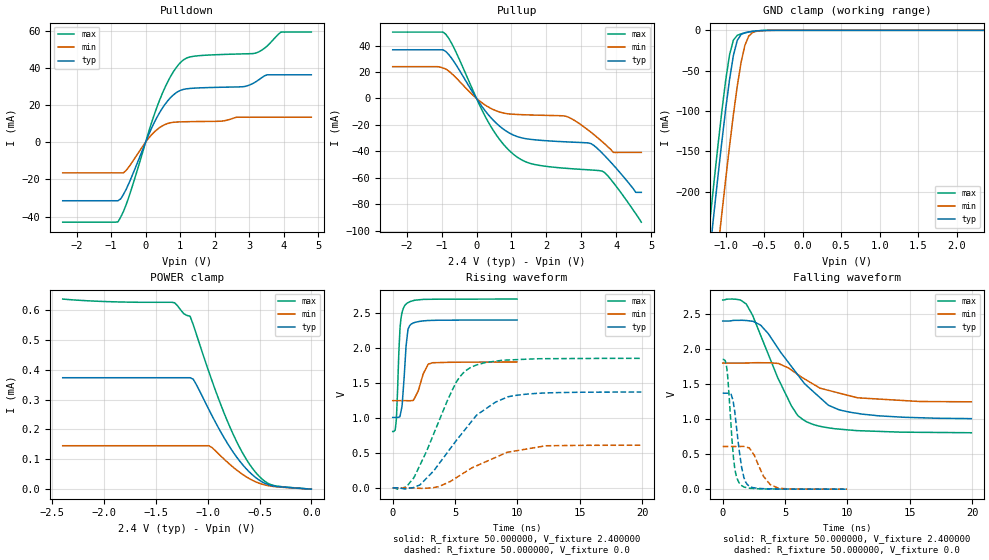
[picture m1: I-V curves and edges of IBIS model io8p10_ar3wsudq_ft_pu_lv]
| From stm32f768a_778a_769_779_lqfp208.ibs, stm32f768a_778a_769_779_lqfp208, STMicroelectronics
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|   Model io8p10_ar3wsudq_ft_pu_lv
[Model]  io8p10_ar3wsudq_ft_pu_lv
Model_type I/O
Polarity   Non-Inverting
Enable   Active-Low
Vinl =   0.720000V
Vinh =   1.680000V
Vmeas =  1.200000V
Cref =   40.000000pF
Rref =   100.000000M
Vref =   0.0V
C_comp   3.720900pF   3.684200pF   3.822900pF
[Temperature Range]   25.000000   0.125000k   -40.000000
[Pullup Reference]   2.400000V   1.800000V   2.700000V
[Pulldown Reference]   0.0V   0.0V   0.0V
[POWER Clamp Reference]   2.400000V   1.800000V   2.700000V
[GND Clamp Reference]   0.0V   0.0V   0.0V
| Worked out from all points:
|   slope of the pulldown table from 0 to 0.36 V, typ, clamps not added: 25 ohm
|   slope of the pullup table from 0 to 0.36 V, typ, clamps not added: 27.7 ohm
|   GND clamp passes 1 mA (typ) near -0.62 V on its own axis
|   rising waveform, R_fixture 50.000000, V_fixture 2.400000: 20-80 % time 333ps typ, 651ps min, 262ps max; typ from 1.01 V to 2.4 V
|   rising waveform, R_fixture 50.000000, V_fixture 0.0: 20-80 % time 3.76ns typ, 4.02ns min, 2.7ns max; typ from 0.001 V to 1.37 V
|   falling waveform, R_fixture 50.000000, V_fixture 2.400000: 20-80 % time 3.91ns typ, 4.04ns min, 2.77ns max; typ from 2.4 V to 1.01 V
|   falling waveform, R_fixture 50.000000, V_fixture 0.0: 20-80 % time 593ps typ, 1.03ns min, 464ps max; typ from 1.37 V to 0.001 V
[Pulldown]
|Voltage   I(typ)   I(min)   I(max)
-2.4V     -31.47mA   -16.45mA   -43.01mA
-800mV    -31.47mA   -16.45mA   -42.85mA
-480mV    -21.98mA   -13.17mA   -29.21mA
80mV      3.63mA     1.966mA    5.014mA
480mV     18.16mA    8.738mA    26.02mA
800mV     25.38mA    10.72mA    37.77mA
1.12V     28.53mA    11.02mA    44.6mA
2.8V      29.84mA    13.47mA    47.53mA
3.2V      32.6mA     13.47mA    48.03mA
3.52V     36.29mA    13.47mA    51.75mA
3.92V     36.29mA    13.47mA    59.26mA
4.8V      36.29mA    13.47mA    59.26mA
[Pullup]
|Voltage   I(typ)   I(min)   I(max)
-2.4V     36.82mA    24.03mA    50.21mA
-960mV    36.82mA    23mA       50.21mA
-640mV    27.62mA    17.03mA    37.94mA
320mV     -11.75mA   -6.207mA   -17.08mA
960mV     -26.47mA   -11.82mA   -40.02mA
1.52V     -30.88mA   -12.51mA   -49.05mA
2.56V     -32.88mA   -13.52mA   -52.9mA
3.28V     -34.25mA   -25.64mA   -54.17mA
3.6V      -41.44mA   -32.74mA   -55.02mA
3.92V     -50.46mA   -40.9mA    -63.78mA
4.56V     -71.1mA    -40.9mA    -87.26mA
4.72V     -71.1mA    -40.9mA    -93.7mA
[GND_clamp]
|Voltage   I(typ)   I(min)   I(max)
-2.4V     -1.43A     -1.515A    -1.399A
-1.25V    -315.9mA   -407.2mA   -278.2mA
-1.2V     -270.1mA   -361.3mA   -232.1mA
-1.15V    -225mA     -316mA     -186.8mA
-1.1V     -180.9mA   -271.3mA   -142.7mA
-1.05V    -138.2mA   -227.5mA   -100.5mA
-950mV    -61.14mA   -143.6mA   -30.43mA
-900mV    -31.23mA   -104.7mA   -12.14mA
-850mV    -12.49mA   -69.4mA    -6.221mA
-750mV    -2.898mA   -18.35mA   -3.18mA
-600mV    -750.2uA   -1.218mA   -738.3uA
2.35V     0A         0A         0A
[POWER_clamp]
|Voltage   I(typ)   I(min)   I(max)
-2.4V     373.1uA    145.5uA    636.5uA
-1.32V    373.1uA    145.5uA    624.2uA
-1.23V    373.1uA    145.5uA    587.2uA
-1.17V    373.1uA    145.5uA    579uA
-1.14V    368.3uA    145.5uA    550.7uA
-990mV    267.3uA    145.5uA    393.9uA
-810mV    153.6uA    90.29uA    227.7uA
-690mV    93.37uA    55.97uA    138.2uA
-570mV    48.37uA    29.94uA    70.44uA
-480mV    25.27uA    17.04uA    35.17uA
-390mV    12.49uA    10.18uA    15.16uA
0V        0A         0A         0A
[Ramp]
| variable   typ   min   max
dV/dt_r  0.82195/3.76236n   0.36591/4.02215n   1.11287/2.70274n
dV/dt_f  0.83262/3.90875n   0.33210/4.10871n   1.13572/2.76916n
R_load = 50.000000
[Rising Waveform]
R_fixture= 50.000000
V_fixture= 2.400000
V_fixture_min= 1.800000
V_fixture_max= 2.700000
|time   V(typ)   V(min)   V(max)
0s        1.007V     1.247V     805.9mV
200.2ps   1.007V     1.247V     831.6mV
280.3ps   1.007V     1.247V     953.6mV
580.6ps   1.02V      1.247V     2.266V
760.8ps   1.194V     1.247V     2.513V
1.021ns   1.882V     1.247V     2.619V
1.241ns   2.273V     1.246V     2.649V
1.762ns   2.364V     1.287V     2.683V
2.863ns   2.393V     1.77V      2.696V
9.97ns    2.4V       1.8V       2.699V
[Rising Waveform]
R_fixture= 50.000000
V_fixture= 0.0
V_fixture_min= 0.0
V_fixture_max= 0.0
|time   V(typ)   V(min)   V(max)
0s        1.04mV     904.1uV    1.025mV
1.081ns   -12.03mV   963.1uV    15.4mV
1.682ns   6.771mV    -78.99uV   142.4mV
3.283ns   243.2mV    4.878mV    770.6mV
5.045ns   665.1mV    140mV      1.496V
6.366ns   960mV      287.9mV    1.731V
8.248ns   1.226V     435.9mV    1.811V
9.61ns    1.315V     521.9mV    1.831V
12.29ns   1.357V     602.5mV    1.847V
19.94ns   1.371V     610.2mV    1.852V
[Falling Waveform]
R_fixture= 50.000000
V_fixture= 2.400000
V_fixture_min= 1.800000
V_fixture_max= 2.700000
|time   V(typ)   V(min)   V(max)
0s        2.4V       1.8V       2.699V
1.361ns   2.41V      1.8V       2.702V
1.882ns   2.407V     1.801V     2.644V
3.043ns   2.341V     1.805V     2.196V
4.484ns   1.998V     1.794V     1.565V
5.526ns   1.748V     1.699V     1.185V
6.687ns   1.486V     1.561V     966.1mV
8.488ns   1.198V     1.41V      876.3mV
10.17ns   1.1V       1.334V     844.9mV
19.94ns   1.007V     1.247V     805.9mV
[Falling Waveform]
R_fixture= 50.000000
V_fixture= 0.0
V_fixture_min= 0.0
V_fixture_max= 0.0
|time   V(typ)   V(min)   V(max)
0s        1.371V     610.2mV    1.852V
320.3ps   1.371V     610.2mV    1.736V
820.8ps   1.272V     610mV      540.8mV
1.061ns   955.8mV    609.8mV    209.5mV
1.421ns   432.1mV    610.3mV    67.14mV
1.702ns   166.2mV    609.8mV    33.21mV
2.062ns   53.3mV     593mV      17.42mV
3.283ns   7.662mV    181.9mV    4.683mV
4.464ns   3.223mV    15.27mV    2.145mV
9.97ns    1.04mV     904.1uV    1.025mV
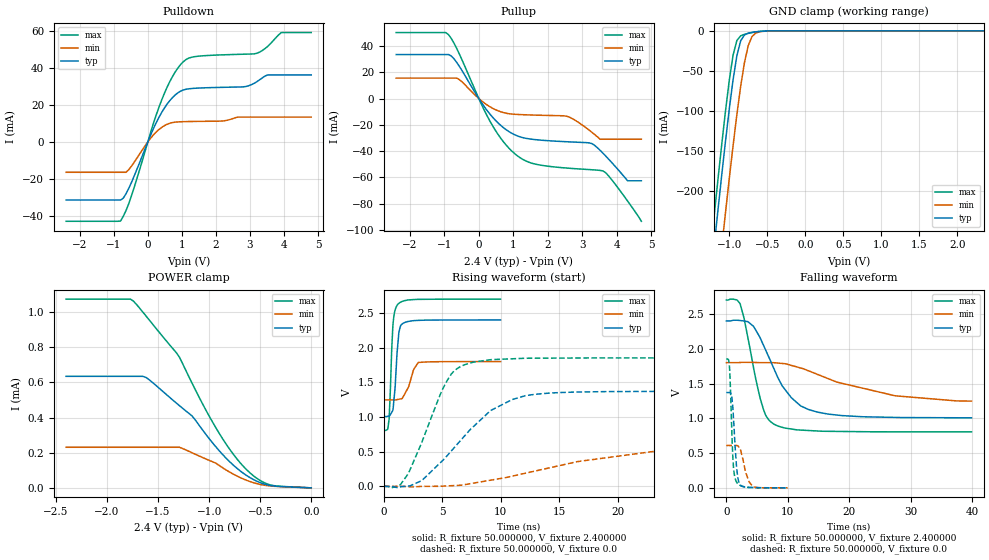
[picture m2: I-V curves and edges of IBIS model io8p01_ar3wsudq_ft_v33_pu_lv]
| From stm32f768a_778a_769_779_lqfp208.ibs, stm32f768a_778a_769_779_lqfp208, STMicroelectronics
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|   Model io8p01_ar3wsudq_ft_v33_pu_lv
[Model]  io8p01_ar3wsudq_ft_v33_pu_lv
Model_type I/O
Polarity   Non-Inverting
Enable   Active-Low
Vinl =   0.720000V
Vinh =   1.680000V
Vmeas =  1.200000V
Cref =   50.000000pF
Rref =   100.000000M
Vref =   0.0V
C_comp   3.737900pF   3.690400pF   3.817400pF
[Temperature Range]   25.000000   0.125000k   -40.000000
[Pullup Reference]   2.400000V   1.800000V   2.700000V
[Pulldown Reference]   0.0V   0.0V   0.0V
[POWER Clamp Reference]   2.400000V   1.800000V   2.700000V
[GND Clamp Reference]   0.0V   0.0V   0.0V
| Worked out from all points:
|   slope of the pulldown table from 0 to 0.36 V, typ, clamps not added: 25 ohm
|   slope of the pullup table from 0 to 0.36 V, typ, clamps not added: 27.7 ohm
|   GND clamp passes 1 mA (typ) near -0.62 V on its own axis
|   rising waveform, R_fixture 50.000000, V_fixture 2.400000: 20-80 % time 349ps typ, 697ps min, 271ps max; typ from 1.01 V to 2.4 V
|   rising waveform, R_fixture 50.000000, V_fixture 0.0: 20-80 % time 4.74ns typ, 12.1ns min, 2.7ns max; typ from 0.001 V to 1.37 V
|   falling waveform, R_fixture 50.000000, V_fixture 2.400000: 20-80 % time 5.04ns typ, 12.6ns min, 2.7ns max; typ from 2.4 V to 1.01 V
|   falling waveform, R_fixture 50.000000, V_fixture 0.0: 20-80 % time 601ps typ, 1.08ns min, 463ps max; typ from 1.37 V to 0.001 V
[Pulldown]
|Voltage   I(typ)   I(min)   I(max)
-2.4V     -31.47mA   -16.45mA   -43.01mA
-800mV    -31.47mA   -16.45mA   -42.85mA
-480mV    -21.98mA   -13.17mA   -29.21mA
80mV      3.63mA     1.966mA    5.014mA
480mV     18.16mA    8.738mA    26.02mA
800mV     25.38mA    10.72mA    37.77mA
1.12V     28.53mA    11.02mA    44.6mA
2.8V      29.84mA    13.47mA    47.53mA
3.2V      32.6mA     13.47mA    48.03mA
3.52V     36.3mA     13.47mA    51.75mA
3.92V     36.3mA     13.47mA    59.27mA
4.8V      36.3mA     13.47mA    59.27mA
[Pullup]
|Voltage   I(typ)   I(min)   I(max)
-2.4V     33.5mA     15.56mA    50.21mA
-960mV    33.5mA     15.56mA    50.21mA
-800mV    32.39mA    15.56mA    45.69mA
-560mV    24.27mA    14.3mA     33.51mA
320mV     -11.75mA   -6.207mA   -17.08mA
960mV     -26.47mA   -11.82mA   -40.02mA
1.52V     -30.88mA   -12.51mA   -49.05mA
2.56V     -32.88mA   -13.52mA   -52.9mA
3.28V     -34.25mA   -25.62mA   -54.17mA
3.6V      -41.44mA   -30.96mA   -55.02mA
4.32V     -62.57mA   -30.96mA   -77.98mA
4.72V     -62.57mA   -30.96mA   -93.4mA
[GND_clamp]
|Voltage   I(typ)   I(min)   I(max)
-2.4V     -1.437A    -1.518A    -1.411A
-1.25V    -315.9mA   -407.2mA   -278.2mA
-1.2V     -270.1mA   -361.3mA   -232.1mA
-1.15V    -225mA     -316mA     -186.8mA
-1.1V     -180.9mA   -271.3mA   -142.7mA
-1.05V    -138.2mA   -227.5mA   -100.5mA
-950mV    -61.14mA   -143.6mA   -30.43mA
-900mV    -31.23mA   -104.7mA   -12.14mA
-850mV    -12.49mA   -69.4mA    -6.221mA
-750mV    -2.898mA   -18.35mA   -3.18mA
-600mV    -750.2uA   -1.218mA   -738.3uA
2.35V     0A         0A         0A
[POWER_clamp]
|Voltage   I(typ)   I(min)   I(max)
-2.4V     634.4uA    230.9uA    1.073mA
-1.77V    634.4uA    230.9uA    1.073mA
-1.74V    634.4uA    230.9uA    1.062mA
-1.62V    628.7uA    230.9uA    979.3uA
-1.29V    467.4uA    230.9uA    743.1uA
-1.17V    410.9uA    200.6uA    599.2uA
-930mV    230.8uA    139uA      338.2uA
-780mV    138.4uA    83.46uA    204.6uA
-660mV    81.05uA    49.28uA    119.5uA
-540mV    39.7uA     25.07uA    57.27uA
-420mV    15.59uA    11.9uA     19.92uA
0V        0A         0A         0A
[Ramp]
| variable   typ   min   max
dV/dt_r  0.82231/4.74010n   0.38222/12.88778n   1.11089/2.69821n
dV/dt_f  0.83616/5.04470n   0.32160/12.69214n   1.13688/2.70258n
R_load = 50.000000
[Rising Waveform]
R_fixture= 50.000000
V_fixture= 2.400000
V_fixture_min= 1.800000
V_fixture_max= 2.700000
|time   V(typ)   V(min)   V(max)
0s        1.007V     1.247V     806mV
320.3ps   1.011V     1.247V     822.7mV
440.4ps   1.016V     1.247V     969.4mV
660.7ps   1.067V     1.247V     1.96V
760.8ps   1.097V     1.247V     2.308V
961ps     1.445V     1.247V     2.545V
1.201ns   2.076V     1.254V     2.628V
1.441ns   2.323V     1.263V     2.658V
2.943ns   2.393V     1.787V     2.696V
9.97ns    2.4V       1.8V       2.7V
[Rising Waveform]
R_fixture= 50.000000
V_fixture= 0.0
V_fixture_min= 0.0
V_fixture_max= 0.0
|time   V(typ)   V(min)   V(max)
0s        967.4uV    875.8uV    1.107mV
1.441ns   -3.909mV   396.7uV    32.55mV
3.203ns   82.27mV    359.1uV    620.7mV
5.365ns   435.5mV    7.37mV     1.514V
6.246ns   604mV      14.66mV    1.696V
7.608ns   855.7mV    46.22mV    1.79V
9.129ns   1.095V     90.07mV    1.827V
13.13ns   1.331V     229.5mV    1.849V
25.23ns   1.371V     552.7mV    1.852V
39.88ns   1.371V     610.3mV    1.852V
[Falling Waveform]
R_fixture= 50.000000
V_fixture= 2.400000
V_fixture_min= 1.800000
V_fixture_max= 2.700000
|time   V(typ)   V(min)   V(max)
0s        2.4V       1.8V       2.7V
2.242ns   2.405V     1.802V     2.646V
4.404ns   2.324V     1.804V     1.738V
5.526ns   2.152V     1.801V     1.281V
6.486ns   1.963V     1.8V       1.032V
7.768ns   1.708V     1.799V     915.5mV
10.57ns   1.297V     1.761V     846.7mV
14.81ns   1.09V      1.632V     818.1mV
27.47ns   1.013V     1.324V     806.5mV
39.88ns   1.007V     1.247V     806mV
[Falling Waveform]
R_fixture= 50.000000
V_fixture= 0.0
V_fixture_min= 0.0
V_fixture_max= 0.0
|time   V(typ)   V(min)   V(max)
0s        1.371V     610.3mV    1.852V
460.5ps   1.371V     610.2mV    1.796V
660.7ps   1.368V     610.1mV    1.449V
860.9ps   1.329V     609.9mV    893.9mV
1.161ns   1.006V     609.7mV    303.4mV
1.602ns   377.1mV    609.7mV    94.62mV
2.222ns   49.9mV     568.8mV    37.55mV
3.143ns   11.7mV     224.6mV    13.38mV
4.344ns   5.49mV     15.82mV    5.194mV
9.97ns    967.4uV    875.8uV    1.107mV
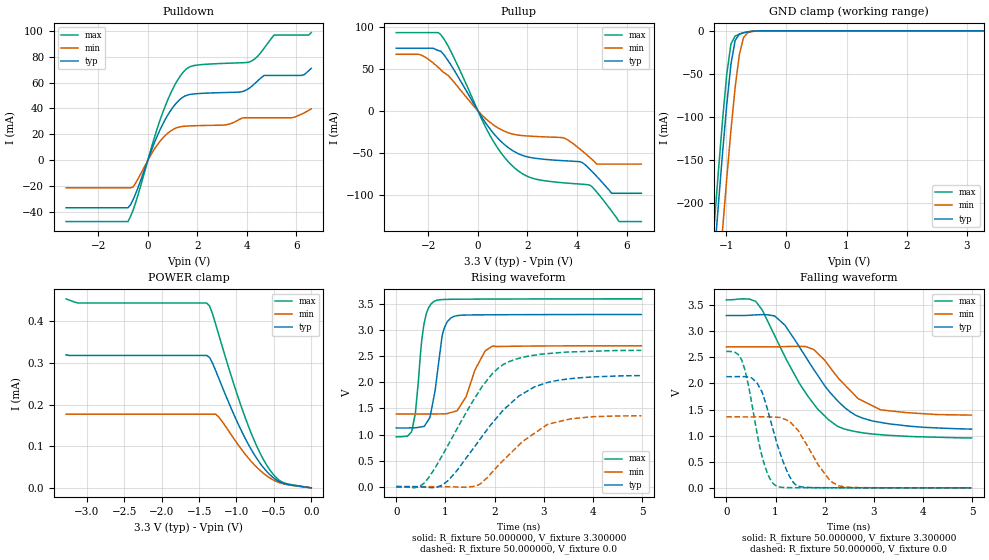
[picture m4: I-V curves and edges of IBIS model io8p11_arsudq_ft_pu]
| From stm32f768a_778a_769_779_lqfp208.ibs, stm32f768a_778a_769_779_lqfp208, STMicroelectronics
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|   Model io8p11_arsudq_ft_pu
[Model]  io8p11_arsudq_ft_pu
Model_type I/O
Polarity   Non-Inverting
Enable   Active-Low
Vinl =   0.990000V
Vinh =   2.310000V
Vmeas =  1.650000V
Cref =   30.000000pF
Rref =   100.000000M
Vref =   0.0V
C_comp   2.292100pF   2.228000pF   2.366600pF
[Temperature Range]   25.000000   0.125000k   -40.000000
[Pullup Reference]   3.300000V   2.700000V   3.600000V
[Pulldown Reference]   0.0V   0.0V   0.0V
[POWER Clamp Reference]   3.300000V   2.700000V   3.600000V
[GND Clamp Reference]   0.0V   0.0V   0.0V
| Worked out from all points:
|   slope of the pulldown table from 0 to 0.495 V, typ, clamps not added: 20.9 ohm
|   slope of the pullup table from 0 to 0.495 V, typ, clamps not added: 22.6 ohm
|   GND clamp passes 1 mA (typ) near -0.62 V on its own axis
|   rising waveform, R_fixture 50.000000, V_fixture 3.300000: 20-80 % time 196ps typ, 341ps min, 160ps max; typ from 1.12 V to 3.3 V
|   rising waveform, R_fixture 50.000000, V_fixture 0.0: 20-80 % time 1.13ns typ, 965ps min, 999ps max; typ from 0.001 V to 2.13 V
|   falling waveform, R_fixture 50.000000, V_fixture 3.300000: 20-80 % time 1.01ns typ, 790ps min, 981ps max; typ from 3.3 V to 1.12 V
|   falling waveform, R_fixture 50.000000, V_fixture 0.0: 20-80 % time 415ps typ, 536ps min, 331ps max; typ from 2.13 V to 0.001 V
[Pulldown]
|Voltage   I(typ)   I(min)   I(max)
-3.3V     -36.46mA   -21.09mA   -47.09mA
-800mV    -36.46mA   -21.09mA   -47.09mA
-600mV    -30.5mA    -20.55mA   -38.69mA
700mV     31.4mA     19.11mA    41.71mA
1.2V      45.15mA    25.37mA    61.75mA
1.6V      50.35mA    26.5mA     71.06mA
3.1V      52.28mA    27.26mA    74.76mA
4.1V      55.64mA    32.87mA    75.8mA
4.7V      65.47mA    32.87mA    86.49mA
5.1V      65.47mA    32.87mA    96.56mA
6.2V      65.47mA    35.57mA    96.56mA
6.6V      70.92mA    39.71mA    98.46mA
[Pullup]
|Voltage   I(typ)   I(min)   I(max)
-3.3V     74.7mA     67.42mA    93.32mA
-2.3V     74.7mA     66.58mA    93.32mA
-1.5V     71.16mA    49mA       90.81mA
500mV     -22.06mA   -14mA      -30.03mA
1.6V      -50.64mA   -28.81mA   -70.96mA
3.5V      -59.52mA   -32.65mA   -85.91mA
4.2V      -61.43mA   -47.48mA   -87.45mA
4.5V      -69.07mA   -55.12mA   -88.37mA
4.8V      -78.22mA   -63.5mA    -96.83mA
5.4V      -98.3mA    -63.5mA    -119.6mA
5.7V      -98.3mA    -63.5mA    -132mA
6.6V      -98.3mA    -63.5mA    -132mA
[GND_clamp]
|Voltage   I(typ)   I(min)   I(max)
-3.3V     -2.316A    -2.396A    -2.289A
-1.2V     -265.5mA   -356.1mA   -227.2mA
-1.13V    -202.6mA   -292.9mA   -164.1mA
-1.06V    -142.2mA   -231.2mA   -104.1mA
-990mV    -85.98mA   -171.6mA   -50.72mA
-920mV    -38.8mA    -115.5mA   -15.28mA
-850mV    -11.08mA   -65.6mA    -6.001mA
-780mV    -3.782mA   -27.42mA   -3.876mA
-710mV    -2.086mA   -7.69mA    -2.381mA
-640mV    -1.147mA   -2.118mA   -1.22mA
-570mV    -523.9uA   -798.4uA   -476.8uA
3.28V     0A         0A         0A
[POWER_clamp]
|Voltage   I(typ)   I(min)   I(max)
-3.28V    319.9uA    177.1uA    454.3uA
-3.12V    318.3uA    177.1uA    444.3uA
-1.4V     318.3uA    177.1uA    444.3uA
-1.36V    313.4uA    177.1uA    437.2uA
-1.28V    282.3uA    177.1uA    394.1uA
-1.24V    264.6uA    170.9uA    369.7uA
-920mV    131.9uA    89.35uA    187.2uA
-760mV    79.47uA    55.13uA    112.7uA
-640mV    48.78uA    35.04uA    68.06uA
-520mV    26.21uA    20.11uA    35uA
-400mV    12.52uA    10.81uA    14.88uA
0V        0A         0A         0A
[Ramp]
| variable   typ   min   max
dV/dt_r  1.26121/1.11649n   0.80589/0.95701n   1.56034/0.99718n
dV/dt_f  1.27626/0.99385n   0.77838/0.78710n   1.56923/0.97409n
R_load = 50.000000
[Rising Waveform]
R_fixture= 50.000000
V_fixture= 3.300000
V_fixture_min= 2.700000
V_fixture_max= 3.600000
|time   V(typ)   V(min)   V(max)
0s        1.125V     1.393V     955.6mV
320.3ps   1.128V     1.393V     1.08V
390.4ps   1.129V     1.393V     1.416V
560.6ps   1.154V     1.393V     3.091V
690.7ps   1.346V     1.393V     3.478V
780.8ps   1.791V     1.393V     3.556V
951ps     2.958V     1.396V     3.586V
1.171ns   3.263V     1.437V     3.591V
1.962ns   3.294V     2.695V     3.595V
4.985ns   3.3V       2.7V       3.599V
[Rising Waveform]
R_fixture= 50.000000
V_fixture= 0.0
V_fixture_min= 0.0
V_fixture_max= 0.0
|time   V(typ)   V(min)   V(max)
0s        1.434mV    1.24mV     1.788mV
470.5ps   -1.714mV   1.179mV    3.241mV
650.7ps   -12.8mV    1.241mV    161.4mV
951ps     40.95mV    15.87uV    623.8mV
1.662ns   854.4mV    29.47mV    1.793V
2.182ns   1.473V     508.9mV    2.343V
2.492ns   1.736V     795.9mV    2.46V
3.083ns   1.998V     1.197V     2.55V
4.004ns   2.103V     1.342V     2.595V
4.985ns   2.129V     1.359V     2.612V
[Falling Waveform]
R_fixture= 50.000000
V_fixture= 3.300000
V_fixture_min= 2.700000
V_fixture_max= 3.600000
|time   V(typ)   V(min)   V(max)
0s        3.3V       2.7V       3.599V
600.6ps   3.312V     2.7V       3.567V
730.7ps   3.316V     2.7V       3.403V
981ps     3.291V     2.701V     2.918V
1.191ns   3.115V     2.704V     2.512V
1.772ns   2.275V     2.651V     1.614V
2.262ns   1.668V     2.118V     1.179V
2.683ns   1.37V      1.707V     1.068V
3.133ns   1.255V     1.495V     1.018V
4.985ns   1.125V     1.393V     955.6mV
[Falling Waveform]
R_fixture= 50.000000
V_fixture= 0.0
V_fixture_min= 0.0
V_fixture_max= 0.0
|time   V(typ)   V(min)   V(max)
0s        2.129V     1.359V     2.612V
310.3ps   2.13V      1.359V     2.454V
450.5ps   2.119V     1.359V     1.96V
720.7ps   1.844V     1.36V      626.8mV
880.9ps   1.352V     1.36V      186.7mV
1.011ns   914mV      1.353V     40.95mV
1.391ns   75.04mV    1.169V     4.403mV
1.872ns   4.587mV    436.1mV    3.191mV
2.282ns   2.973mV    41.02mV    2.805mV
4.985ns   1.434mV    1.24mV     1.788mV
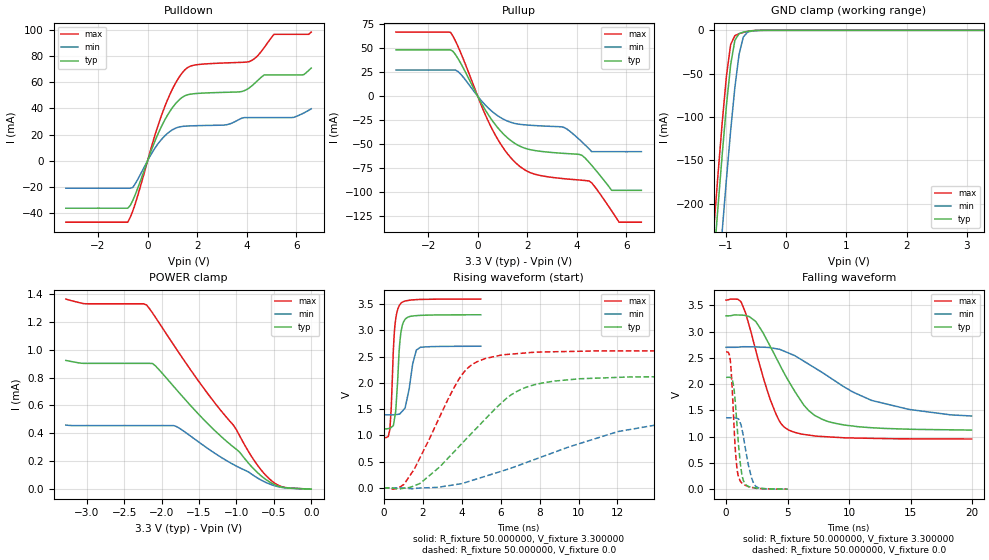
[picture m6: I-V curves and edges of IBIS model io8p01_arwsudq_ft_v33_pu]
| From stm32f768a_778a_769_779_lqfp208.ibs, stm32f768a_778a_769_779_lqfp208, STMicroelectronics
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|   Model io8p01_arwsudq_ft_v33_pu
[Model]  io8p01_arwsudq_ft_v33_pu
Model_type I/O
Polarity   Non-Inverting
Enable   Active-Low
Vinl =   0.990000V
Vinh =   2.310000V
Vmeas =  1.650000V
Cref =   50.000000pF
Rref =   100.000000M
Vref =   0.0V
C_comp   2.911600pF   2.826700pF   2.983100pF
[Temperature Range]   25.000000   0.125000k   -40.000000
[Pullup Reference]   3.300000V   2.700000V   3.600000V
[Pulldown Reference]   0.0V   0.0V   0.0V
[POWER Clamp Reference]   3.300000V   2.700000V   3.600000V
[GND Clamp Reference]   0.0V   0.0V   0.0V
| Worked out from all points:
|   slope of the pulldown table from 0 to 0.495 V, typ, clamps not added: 20.9 ohm
|   slope of the pullup table from 0 to 0.495 V, typ, clamps not added: 22.6 ohm
|   GND clamp passes 1 mA (typ) near -0.62 V on its own axis
|   rising waveform, R_fixture 50.000000, V_fixture 3.300000: 20-80 % time 219ps typ, 367ps min, 188ps max; typ from 1.12 V to 3.3 V
|   rising waveform, R_fixture 50.000000, V_fixture 0.0: 20-80 % time 3.35ns typ, 6.59ns min, 2.1ns max; typ from 0.001 V to 2.13 V
|   falling waveform, R_fixture 50.000000, V_fixture 3.300000: 20-80 % time 3.22ns typ, 6.15ns min, 2.03ns max; typ from 3.3 V to 1.12 V
|   falling waveform, R_fixture 50.000000, V_fixture 0.0: 20-80 % time 464ps typ, 672ps min, 373ps max; typ from 2.13 V to 0.001 V
[Pulldown]
|Voltage   I(typ)   I(min)   I(max)
-3.3V     -36.38mA   -21.07mA   -47.09mA
-800mV    -36.38mA   -21.07mA   -47.09mA
-600mV    -30.5mA    -20.54mA   -38.69mA
700mV     31.4mA     19.11mA    41.71mA
1.2V      45.15mA    25.37mA    61.75mA
1.6V      50.35mA    26.5mA     71.06mA
3.1V      52.28mA    27.26mA    74.76mA
4.1V      55.65mA    32.94mA    75.79mA
4.7V      65.59mA    32.94mA    86.49mA
5.1V      65.59mA    32.94mA    96.67mA
6.3V      65.82mA    36.48mA    96.67mA
6.6V      70.87mA    39.69mA    98.38mA
[Pullup]
|Voltage   I(typ)   I(min)   I(max)
-3.3V     48.41mA    27.39mA    66.93mA
-1.1V     48.41mA    27.39mA    66.7mA
-700mV    35.09mA    23.45mA    46.27mA
500mV     -22.06mA   -14mA      -30.03mA
1.5V      -49.1mA    -28.3mA    -68.56mA
2.2V      -56.04mA   -30.32mA   -80.35mA
3.5V      -59.52mA   -32.65mA   -85.91mA
4.2V      -61.45mA   -47.47mA   -87.45mA
4.5V      -69.09mA   -55.01mA   -88.4mA
5.4V      -98mA      -57.7mA    -119.3mA
5.7V      -98mA      -57.7mA    -131.2mA
6.6V      -98mA      -57.7mA    -131.2mA
[GND_clamp]
|Voltage   I(typ)   I(min)   I(max)
-3.3V     -2.32A     -2.397A    -2.297A
-1.2V     -266.4mA   -356.3mA   -229.4mA
-1.13V    -203.6mA   -293.1mA   -166.3mA
-1.06V    -143.2mA   -231.4mA   -106.2mA
-990mV    -86.95mA   -171.8mA   -52.65mA
-920mV    -39.66mA   -115.8mA   -16.36mA
-850mV    -11.49mA   -65.84mA   -6.11mA
-780mV    -3.834mA   -27.59mA   -3.88mA
-710mV    -2.09mA    -7.753mA   -2.381mA
-640mV    -1.147mA   -2.129mA   -1.22mA
-570mV    -523.9uA   -800uA     -476.8uA
3.28V     0A         0A         0A
[POWER_clamp]
|Voltage   I(typ)   I(min)   I(max)
-3.28V    922.4uA    459.4uA    1.362mA
-3.04V    901.4uA    455.8uA    1.329mA
-2.2V     901.4uA    455.8uA    1.319mA
-2.08V    882.2uA    455.8uA    1.23mA
-1.8V     712.4uA    448.4uA    1.003mA
-1.4V     478.6uA    298uA      696.5uA
-1.04V    302.3uA    176.6uA    458.6uA
-800mV    163uA      108.7uA    236.3uA
-640mV    82.53uA    56.82uA    118.4uA
-520mV    40.35uA    29.6uA     55.89uA
-400mV    15.52uA    13.26uA    18.69uA
0V        0A         0A         0A
[Ramp]
| variable   typ   min   max
dV/dt_r  1.27741/3.34507n   0.80115/6.62068n   1.56664/2.09795n
dV/dt_f  1.30182/3.21657n   0.74286/6.19261n   1.58713/2.03064n
R_load = 50.000000
[Rising Waveform]
R_fixture= 50.000000
V_fixture= 3.300000
V_fixture_min= 2.700000
V_fixture_max= 3.600000
|time   V(typ)   V(min)   V(max)
0s        1.125V     1.393V     955.5mV
320.3ps   1.134V     1.393V     1.124V
390.4ps   1.154V     1.393V     1.532V
500.5ps   1.189V     1.393V     2.647V
620.6ps   1.468V     1.398V     3.224V
850.9ps   2.849V     1.419V     3.502V
1.101ns   3.212V     1.523V     3.561V
1.491ns   3.276V     2.367V     3.584V
1.682ns   3.283V     2.628V     3.588V
4.985ns   3.3V       2.7V       3.599V
[Rising Waveform]
R_fixture= 50.000000
V_fixture= 0.0
V_fixture_min= 0.0
V_fixture_max= 0.0
|time   V(typ)   V(min)   V(max)
0s        1.287mV    1.127mV    1.858mV
1.041ns   -5.54mV    -3.433mV   67.7mV
1.882ns   89.34mV    -1.2mV     588.3mV
3.924ns   810.4mV    77.03mV    2.107V
5.205ns   1.308V     220.3mV    2.464V
6.847ns   1.84V      418.7mV    2.559V
8.769ns   2.036V     681.1mV    2.595V
12.01ns   2.106V     1.072V     2.611V
14.81ns   2.121V     1.253V     2.612V
19.94ns   2.129V     1.36V      2.612V
[Falling Waveform]
R_fixture= 50.000000
V_fixture= 3.300000
V_fixture_min= 2.700000
V_fixture_max= 3.600000
|time   V(typ)   V(min)   V(max)
0s        3.3V       2.7V       3.599V
1.241ns   3.313V     2.709V     3.552V
2.402ns   3.192V     2.708V     2.653V
3.564ns   2.729V     2.692V     1.722V
4.324ns   2.386V     2.663V     1.301V
5.045ns   2.073V     2.594V     1.132V
6.727ns   1.493V     2.378V     1.03V
8.448ns   1.278V     2.123V     994.3mV
11.81ns   1.171V     1.69V      968.2mV
19.94ns   1.125V     1.393V     955.5mV
[Falling Waveform]
R_fixture= 50.000000
V_fixture= 0.0
V_fixture_min= 0.0
V_fixture_max= 0.0
|time   V(typ)   V(min)   V(max)
0s        2.129V     1.36V      2.612V
340.3ps   2.126V     1.359V     2.462V
550.6ps   2.047V     1.359V     1.676V
680.7ps   1.833V     1.359V     1.043V
840.8ps   1.375V     1.351V     494.6mV
1.101ns   627.5mV    1.291V     183.1mV
1.461ns   138.2mV    930.3mV    87.12mV
1.832ns   51.96mV    443.1mV    47.68mV
2.362ns   25.71mV    69.48mV    21.16mV
4.985ns   1.287mV    1.127mV    1.858mV
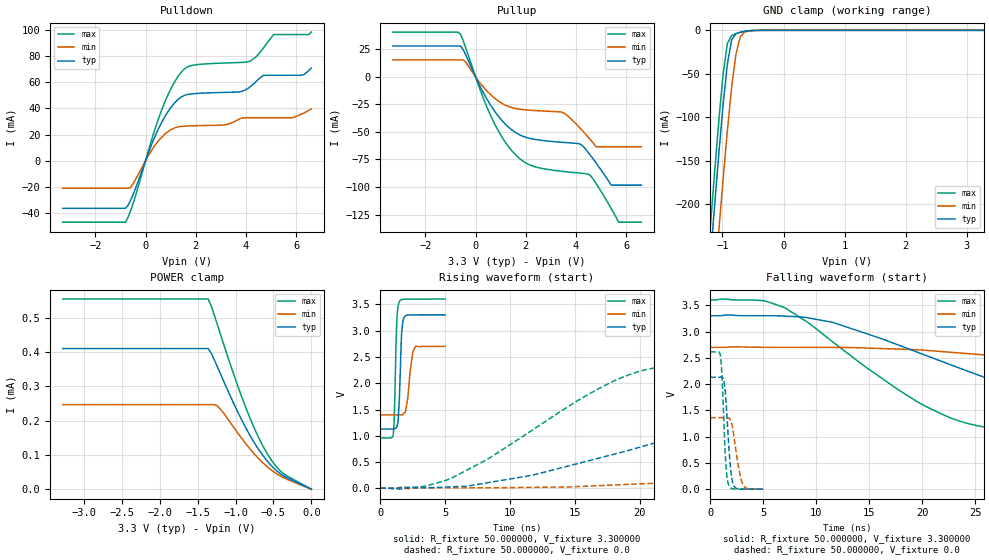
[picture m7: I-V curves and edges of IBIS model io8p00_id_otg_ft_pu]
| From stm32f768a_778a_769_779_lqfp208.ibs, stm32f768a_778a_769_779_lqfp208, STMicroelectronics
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|   Model io8p00_id_otg_ft_pu
[Model]  io8p00_id_otg_ft_pu
Model_type I/O
Polarity   Non-Inverting
Enable   Active-Low
Vinl =   0.990000V
Vinh =   2.310000V
Vmeas =  1.650000V
Cref =   50.000000pF
Rref =   100.000000M
Vref =   0.0V
C_comp   2.282200pF   2.214200pF   2.357400pF
[Temperature Range]   25.000000   0.125000k   -40.000000
[Pullup Reference]   3.300000V   2.700000V   3.600000V
[Pulldown Reference]   0.0V   0.0V   0.0V
[POWER Clamp Reference]   3.300000V   2.700000V   3.600000V
[GND Clamp Reference]   0.0V   0.0V   0.0V
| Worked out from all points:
|   slope of the pulldown table from 0 to 0.495 V, typ, clamps not added: 20.9 ohm
|   slope of the pullup table from 0 to 0.495 V, typ, clamps not added: 22.6 ohm
|   GND clamp passes 1 mA (typ) near -0.62 V on its own axis
|   rising waveform, R_fixture 50.000000, V_fixture 3.300000: 20-80 % time 190ps typ, 343ps min, 163ps max; typ from 1.13 V to 3.3 V
|   rising waveform, R_fixture 50.000000, V_fixture 0.0: 20-80 % time 19.8ns typ, 51.1ns min, 10.4ns max; typ from 0.004 V to 2.13 V
|   falling waveform, R_fixture 50.000000, V_fixture 3.300000: 20-80 % time 18.9ns typ, 44.5ns min, 11.4ns max; typ from 3.3 V to 1.13 V
|   falling waveform, R_fixture 50.000000, V_fixture 0.0: 20-80 % time 433ps typ, 632ps min, 342ps max; typ from 2.13 V to 0.004 V
[Pulldown]
|Voltage   I(typ)   I(min)   I(max)
-3.3V     -36.46mA   -21.09mA   -47.09mA
-800mV    -36.46mA   -21.09mA   -47.09mA
-600mV    -30.5mA    -20.54mA   -38.69mA
700mV     31.4mA     19.11mA    41.71mA
1.2V      45.15mA    25.37mA    61.75mA
1.6V      50.35mA    26.5mA     71.05mA
3.1V      52.28mA    27.26mA    74.75mA
4.1V      55.64mA    32.83mA    75.8mA
4.7V      65.4mA     32.83mA    86.49mA
5.1V      65.4mA     32.83mA    96.56mA
6.2V      65.4mA     35.57mA    96.56mA
6.6V      70.92mA    39.71mA    98.46mA
[Pullup]
|Voltage   I(typ)   I(min)   I(max)
-3.3V     28.01mA    15.42mA    40.63mA
-700mV    28.01mA    15.42mA    40.63mA
-400mV    20.3mA     13.47mA    26.92mA
600mV     -25.76mA   -16.22mA   -35.13mA
1.6V      -50.63mA   -28.8mA    -70.94mA
3.5V      -59.51mA   -32.64mA   -85.89mA
4.2V      -61.41mA   -47.47mA   -87.43mA
4.5V      -69.05mA   -55.11mA   -88.35mA
4.8V      -78.2mA    -63.4mA    -96.8mA
5.4V      -98.3mA    -63.4mA    -119.5mA
5.7V      -98.3mA    -63.4mA    -131.9mA
6.6V      -98.3mA    -63.4mA    -131.9mA
[GND_clamp]
|Voltage   I(typ)   I(min)   I(max)
-3.3V     -2.319A    -2.398A    -2.292A
-1.2V     -265.5mA   -356.1mA   -227.2mA
-1.13V    -202.7mA   -292.9mA   -164.1mA
-1.06V    -142.2mA   -231.2mA   -104.1mA
-990mV    -85.98mA   -171.6mA   -50.73mA
-920mV    -38.81mA   -115.5mA   -15.3mA
-850mV    -11.1mA    -65.61mA   -6.021mA
-780mV    -3.796mA   -27.43mA   -3.892mA
-710mV    -2.096mA   -7.699mA   -2.393mA
-640mV    -1.154mA   -2.125mA   -1.227mA
-570mV    -528.1uA   -803.6uA   -480.7uA
3.28V     0A         0A         0A
[POWER_clamp]
|Voltage   I(typ)   I(min)   I(max)
-3.28V    410.1uA    246.5uA    554.5uA
-1.36V    410.1uA    246.5uA    554.5uA
-1.32V    396.3uA    246.5uA    534.1uA
-1.28V    377.3uA    246.5uA    507.5uA
-1.2V     337.1uA    233.5uA    452.5uA
-1.04V    257.7uA    185.3uA    345.3uA
-880mV    185.4uA    137uA      247uA
-760mV    138.3uA    104.8uA    181.8uA
-640mV    98.44uA    77.14uA    126.4uA
-520mV    66.65uA    54.47uA    82.45uA
-400mV    43.68uA    37.32uA    51.43uA
0V        0A         0A         0A
[Ramp]
| variable   typ   min   max
dV/dt_r  1.27632/19.76560n   0.81522/51.12287n   1.56555/10.38857n
dV/dt_f  1.30410/18.95004n   0.78174/44.58919n   1.58471/11.36702n
R_load = 50.000000
[Rising Waveform]
R_fixture= 50.000000
V_fixture= 3.300000
V_fixture_min= 2.700000
V_fixture_max= 3.600000
|time   V(typ)   V(min)   V(max)
0s        1.129V     1.397V     958.8mV
1.001ns   1.131V     1.397V     1.023V
1.071ns   1.133V     1.397V     1.294V
1.281ns   1.175V     1.397V     3.214V
1.461ns   1.668V     1.396V     3.547V
1.632ns   2.89V      1.399V     3.589V
1.862ns   3.262V     1.436V     3.596V
2.503ns   3.298V     2.589V     3.599V
2.723ns   3.299V     2.702V     3.599V
4.985ns   3.3V       2.7V       3.6V
[Rising Waveform]
R_fixture= 50.000000
V_fixture= 0.0
V_fixture_min= 0.0
V_fixture_max= 0.0
|time   V(typ)   V(min)   V(max)
0s        4.494mV    4.193mV    4.742mV
5.506ns   30.3mV     11.57mV    196.8mV
11.51ns   242.2mV    19.88mV    1.077V
19.02ns   715.7mV    76.09mV    2.148V
28.03ns   1.341V     182.9mV    2.499V
36.54ns   1.798V     334.2mV    2.569V
46.05ns   1.989V     503.3mV    2.596V
89.09ns   2.121V     1.145V     2.614V
117.6ns   2.132V     1.303V     2.614V
249.2ns   2.132V     1.363V     2.614V
[Falling Waveform]
R_fixture= 50.000000
V_fixture= 3.300000
V_fixture_min= 2.700000
V_fixture_max= 3.600000
|time   V(typ)   V(min)   V(max)
0s        3.3V       2.7V       3.6V
5.506ns   3.3V       2.7V       3.561V
11.51ns   3.176V     2.697V     2.809V
22.52ns   2.379V     2.608V     1.369V
31.53ns   1.731V     2.432V     1.08V
41.54ns   1.354V     2.2V       1.016V
50.05ns   1.25V      2.012V     994.4mV
81.58ns   1.157V     1.591V     962.2mV
107.1ns   1.14V      1.467V     959.9mV
249.2ns   1.129V     1.397V     958.8mV
[Falling Waveform]
R_fixture= 50.000000
V_fixture= 0.0
V_fixture_min= 0.0
V_fixture_max= 0.0
|time   V(typ)   V(min)   V(max)
0s        2.132V     1.363V     2.614V
981ps     2.133V     1.362V     2.508V
1.151ns   2.123V     1.362V     1.945V
1.411ns   1.872V     1.363V     683.3mV
1.542ns   1.49V      1.365V     295.2mV
1.732ns   863.9mV    1.358V     83.64mV
2.152ns   102.3mV    1.123V     11.04mV
2.573ns   13.84mV    528.3mV    5.615mV
3.123ns   5.326mV    76.65mV    4.812mV
4.985ns   4.494mV    4.193mV    4.742mV
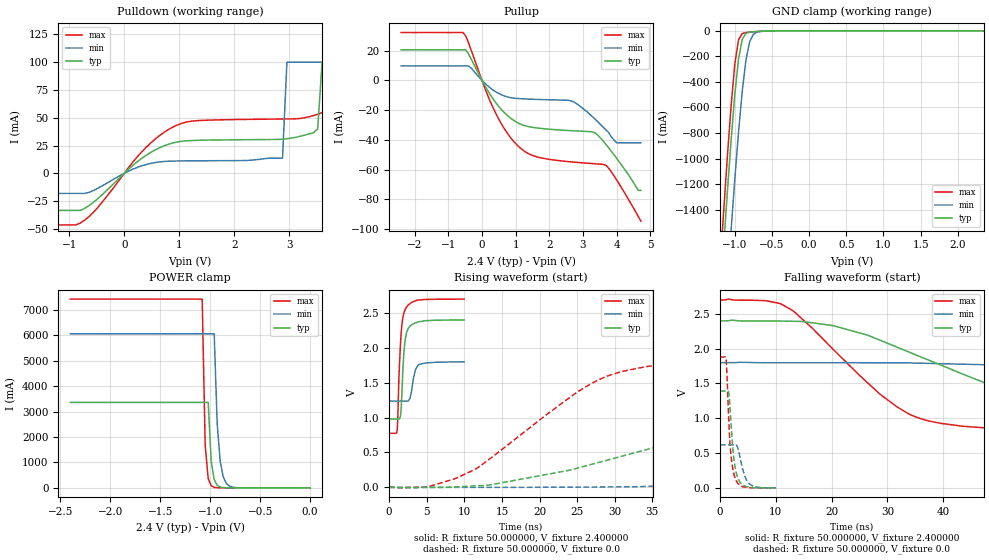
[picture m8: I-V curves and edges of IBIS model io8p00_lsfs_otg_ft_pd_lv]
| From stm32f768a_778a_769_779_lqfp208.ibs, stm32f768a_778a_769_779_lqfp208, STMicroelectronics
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|   Model io8p00_lsfs_otg_ft_pd_lv
[Model]  io8p00_lsfs_otg_ft_pd_lv
Model_type I/O
Polarity   Non-Inverting
Enable   Active-Low
Vinl =   0.720000V
Vinh =   1.680000V
Vmeas =  1.200000V
Cref =   50.000000pF
Rref =   100.000000M
Vref =   0.0V
C_comp   7.971100pF   7.737700pF   8.264100pF
[Temperature Range]   25.000000   0.125000k   -40.000000
[Pullup Reference]   2.400000V   1.800000V   2.700000V
[Pulldown Reference]   0.0V   0.0V   0.0V
[POWER Clamp Reference]   2.400000V   1.800000V   2.700000V
[GND Clamp Reference]   0.0V   0.0V   0.0V
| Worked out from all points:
|   slope of the pulldown table from 0 to 0.36 V, typ, clamps not added: 24.1 ohm
|   slope of the pullup table from 0 to 0.36 V, typ, clamps not added: 26.8 ohm
|   GND clamp passes 1 mA (typ) near -0.52 V on its own axis
|   POWER clamp passes 1 mA (typ) near -0.81 V on its own axis
|   rising waveform, R_fixture 50.000000, V_fixture 2.400000: 20-80 % time 476ps typ, 591ps min, 488ps max; typ from 0.981 V to 2.4 V
|   rising waveform, R_fixture 50.000000, V_fixture 0.0: 20-80 % time 30.9ns typ, 82ns min, 14.2ns max; typ from 0 V to 1.39 V
|   falling waveform, R_fixture 50.000000, V_fixture 2.400000: 20-80 % time 28.5ns typ, 70.3ns min, 15.5ns max; typ from 2.4 V to 0.981 V
|   falling waveform, R_fixture 50.000000, V_fixture 0.0: 20-80 % time 911ps typ, 1.27ns min, 794ps max; typ from 1.39 V to 0 V
[Pulldown]
|Voltage   I(typ)   I(min)   I(max)
-2.4V     -33.44mA   -18.11mA   -46.52mA
-800mV    -33.44mA   -18.11mA   -44.78mA
1.04V     28.81mA    11.13mA    44.91mA
2.88V     30.7mA     13.64mA    48.89mA
2.96V     31.11mA    100mA      48.94mA
3.52V     40mA       100mA      53.15mA
3.6V      100mA      100mA      54.65mA
3.92V     100mA      100mA      60mA
4V        100mA      100mA      100mA
4.4V      100mA      100mA      100mA
4.48V     100mA      100mA      1A
4.8V      100mA      100mA      1A
[Pullup]
|Voltage   I(typ)   I(min)   I(max)
-2.4V     20.56mA    9.685mA    32.17mA
-560mV    20.56mA    9.685mA    32.17mA
-400mV    17.86mA    9.685mA    25.31mA
320mV     -12.14mA   -6.322mA   -17.91mA
960mV     -27.18mA   -12mA      -41.54mA
1.52V     -31.65mA   -12.71mA   -50.68mA
2.64V     -33.82mA   -13.73mA   -54.81mA
3.36V     -35.34mA   -26.1mA    -56.1mA
3.68V     -43.1mA    -33.3mA    -57.12mA
4V        -52.4mA    -42mA      -67mA
4.64V     -74mA      -42mA      -91.5mA
4.72V     -74mA      -42mA      -94.8mA
[GND_clamp]
|Voltage   I(typ)   I(min)   I(max)
-2.4V     -9.766A    -9.942A    -9.572A
-1.2V     -2.124A    -2.851A    -1.855A
-1.15V    -1.682A    -2.408A    -1.408A
-1.1V     -1.256A    -1.975A    -979.8mA
-1.05V    -854.9mA   -1.557A    -584.5mA
-1V       -496.5mA   -1.158A    -257.5mA
-950mV    -217.7mA   -789.7mA   -69.53mA
-900mV    -65.58mA   -469.8mA   -21.52mA
-850mV    -19.65mA   -226.4mA   -13.58mA
-800mV    -9.766mA   -84.22mA   -10.49mA
-700mV    -4.935mA   -9.894mA   -5.821mA
2.35V     58.09uA    37.92uA    67.25uA
[POWER_clamp]
|Voltage   I(typ)   I(min)   I(max)
-2.4V     3.365A     6.064A     7.43A
-1.08V    3.365A     6.064A     7.43A
-1.05V    3.365A     6.064A     1.669A
-1.02V    3.365A     6.064A     375mA
-990mV    1.047A     6.064A     84.24mA
-960mV    325.6mA    6.064A     18.93mA
-930mV    101.3mA    2.529A     4.252mA
-900mV    31.51mA    1.055A     955.2uA
-870mV    9.804mA    440.1mA    214.6uA
-840mV    3.05mA     183.6mA    74uA
-720mV    28.58uA    5.557mA    74uA
0V        0A         0A         0A
[Ramp]
| variable   typ   min   max
dV/dt_r  0.83514/30.91383n   0.36531/82.45258n   1.12794/14.18332n
dV/dt_f  0.85113/28.50033n   0.33228/72.08627n   1.15499/15.51310n
R_load = 50.000000
[Rising Waveform]
R_fixture= 50.000000
V_fixture= 2.400000
V_fixture_min= 1.800000
V_fixture_max= 2.700000
|time   V(typ)   V(min)   V(max)
0s        980.5mV    1.238V     774.4mV
1.061ns   980.4mV    1.238V     814.6mV
1.141ns   980.1mV    1.238V     974.5mV
1.341ns   982.4mV    1.238V     1.687V
1.562ns   1.085V     1.238V     2.156V
1.942ns   1.905V     1.237V     2.493V
2.182ns   2.151V     1.236V     2.562V
2.783ns   2.312V     1.281V     2.636V
3.824ns   2.37V      1.752V     2.684V
9.97ns    2.399V     1.799V     2.699V
[Rising Waveform]
R_fixture= 50.000000
V_fixture= 0.0
V_fixture_min= 0.0
V_fixture_max= 0.0
|time   V(typ)   V(min)   V(max)
0s        3.299uV    1.719uV    7.415uV
5.005ns   -279.5uV   -687uV     4.285mV
11.51ns   20.84mV    -38.23uV   262.4mV
24.52ns   260.6mV    3.533mV    1.328V
29.03ns   391.1mV    5.855mV    1.597V
41.54ns   759.6mV    36.49mV    1.811V
62.06ns   1.212V     102.1mV    1.866V
82.08ns   1.341V     202.2mV    1.879V
165.7ns   1.391V     547.7mV    1.88V
249.2ns   1.391V     617.3mV    1.88V
[Falling Waveform]
R_fixture= 50.000000
V_fixture= 2.400000
V_fixture_min= 1.800000
V_fixture_max= 2.700000
|time   V(typ)   V(min)   V(max)
0s        2.399V     1.799V     2.699V
11.01ns   2.396V     1.798V     2.64V
20.52ns   2.325V     1.798V     1.971V
32.03ns   2.011V     1.796V     1.147V
36.54ns   1.863V     1.79V      979.8mV
43.54ns   1.633V     1.777V     885.1mV
60.06ns   1.223V     1.719V     818.6mV
86.09ns   1.053V     1.564V     786.3mV
158.7ns   988.1mV    1.292V     774.7mV
249.2ns   980.5mV    1.238V     774.4mV
[Falling Waveform]
R_fixture= 50.000000
V_fixture= 0.0
V_fixture_min= 0.0
V_fixture_max= 0.0
|time   V(typ)   V(min)   V(max)
0s        1.391V     617.3mV    1.88V
1.081ns   1.392V     617.3mV    1.85V
1.522ns   1.377V     617.3mV    1.074V
1.842ns   1.099V     616.8mV    583mV
2.402ns   479.5mV    618.4mV    229.5mV
2.763ns   269.7mV    621.5mV    125.5mV
3.524ns   87.62mV    460.2mV    43.56mV
4.484ns   25.64mV    161mV      11.2mV
5.285ns   11.28mV    55.56mV    3.714mV
9.97ns    3.299uV    1.719uV    7.415uV
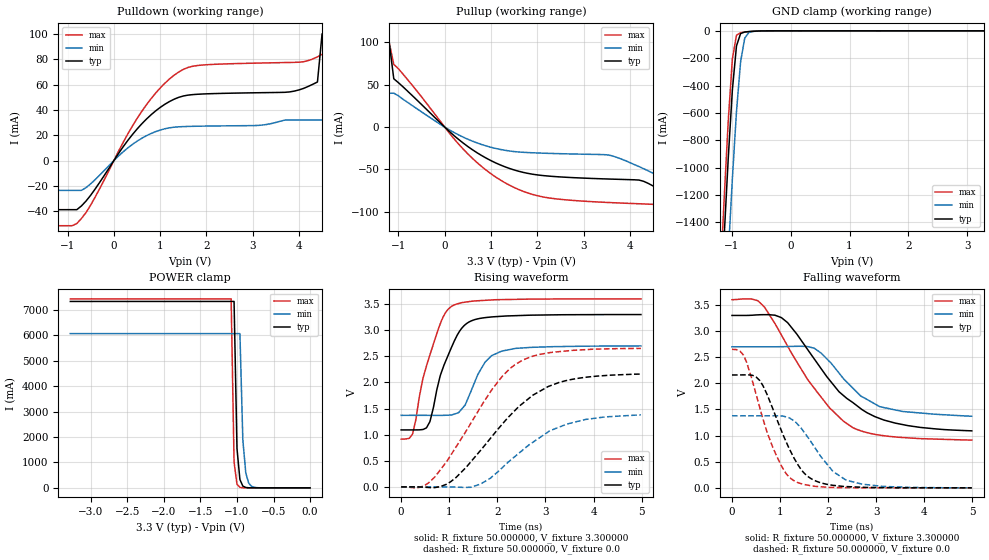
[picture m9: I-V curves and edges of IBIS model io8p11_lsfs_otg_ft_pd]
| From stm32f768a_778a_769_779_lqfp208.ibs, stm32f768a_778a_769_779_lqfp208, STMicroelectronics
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|   Model io8p11_lsfs_otg_ft_pd
[Model]  io8p11_lsfs_otg_ft_pd
Model_type I/O
Polarity   Non-Inverting
Enable   Active-Low
Vinl =   0.990000V
Vinh =   2.310000V
Vmeas =  1.650000V
Cref =   30.000000pF
Rref =   100.000000M
Vref =   0.0V
C_comp   8.196500pF   7.968500pF   8.492600pF
[Temperature Range]   25.000000   0.125000k   -40.000000
[Pullup Reference]   3.300000V   2.700000V   3.600000V
[Pulldown Reference]   0.0V   0.0V   0.0V
[POWER Clamp Reference]   3.300000V   2.700000V   3.600000V
[GND Clamp Reference]   0.0V   0.0V   0.0V
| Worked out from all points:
|   slope of the pulldown table from 0 to 0.495 V, typ, clamps not added: 20.1 ohm
|   slope of the pullup table from 0 to 0.495 V, typ, clamps not added: 21.8 ohm
|   GND clamp passes 1 mA (typ) near -0.52 V on its own axis
|   POWER clamp passes 1 mA (typ) near -0.81 V on its own axis
|   rising waveform, R_fixture 50.000000, V_fixture 3.300000: 20-80 % time 466ps typ, 431ps min, 456ps max; typ from 1.09 V to 3.3 V
|   rising waveform, R_fixture 50.000000, V_fixture 0.0: 20-80 % time 1.3ns typ, 1.18ns min, 1.13ns max; typ from 0 V to 2.16 V
|   falling waveform, R_fixture 50.000000, V_fixture 3.300000: 20-80 % time 1.24ns typ, 905ps min, 1.17ns max; typ from 3.3 V to 1.09 V
|   falling waveform, R_fixture 50.000000, V_fixture 0.0: 20-80 % time 622ps typ, 690ps min, 569ps max; typ from 2.16 V to 0 V
[Pulldown]
|Voltage   I(typ)   I(min)   I(max)
-3.3V     -38.65mA   -23.43mA   -51.3mA
-800mV    -38.65mA   -23.43mA   -49.55mA
600mV     28.88mA    17.56mA    38.65mA
1.4V      49.88mA    26.66mA    69.84mA
4.1V      56.96mA    32mA       77.99mA
4.4V      62mA       32mA       81.8mA
4.5V      100mA      32mA       83.9mA
4.7V      100mA      32mA       89mA
4.8V      100mA      32mA       100mA
5.1V      100mA      32mA       100mA
5.2V      1A         1A         100mA
6.6V      1A         1A         1A
[Pullup]
|Voltage   I(typ)   I(min)   I(max)
-3.3V     1A         1A         100mA
-1.9V     1A         1A         100mA
-1.8V     100mA      1A         100mA
-1.6V     100mA      1A         100mA
-1.5V     100mA      40mA       100mA
-1.2V     100mA      40mA       100mA
-1.1V     57mA       40mA       74mA
500mV     -22.94mA   -14.36mA   -31.63mA
1.6V      -52.16mA   -29.4mA    -73.72mA
4.2V      -62.54mA   -46.6mA    -90.53mA
5.5V      -103mA     -65mA      -126.2mA
6.6V      -103mA     -65mA      -140mA
[GND_clamp]
|Voltage   I(typ)   I(min)   I(max)
-3.3V     -9.479A    -9.465A    -9.974A
-1.2V     -2.125A    -2.854A    -1.857A
-1.13V    -1.511A    -2.236A    -1.236A
-1.06V    -933.3mA   -1.641A    -660.9mA
-990mV    -433.3mA   -1.082A    -207mA
-920mV    -110.3mA   -591mA     -31.46mA
-850mV    -19.8mA    -226.8mA   -13.66mA
-780mV    -8.323mA   -53.94mA   -9.521mA
-710mV    -5.297mA   -11.95mA   -6.277mA
-640mV    -3.244mA   -4.292mA   -3.591mA
3.28V     81.28uA    57.87uA    93.98uA
[POWER_clamp]
|Voltage   I(typ)   I(min)   I(max)
-3.28V    7.328A     6.064A     7.43A
-1.08V    7.328A     6.064A     7.43A
-1.04V    7.328A     6.064A     1.015A
-1V       1.545A     6.064A     138.6mA
-960mV    325.6mA    6.064A     18.93mA
-920mV    68.64mA    1.89A      2.585mA
-880mV    14.47mA    589mA      353uA
-840mV    3.05mA     183.6mA    105.2uA
-800mV    642.9uA    57.21mA    105.2uA
-720mV    28.59uA    5.557mA    105.2uA
0V        0A         0A         0A
[Ramp]
| variable   typ   min   max
dV/dt_r  1.26767/1.27166n   0.78762/1.10603n   1.58071/1.12045n
dV/dt_f  1.28424/1.20532n   0.74892/0.85167n   1.59048/1.16332n
R_load = 50.000000
[Rising Waveform]
R_fixture= 50.000000
V_fixture= 3.300000
V_fixture_min= 2.700000
V_fixture_max= 3.600000
|time   V(typ)   V(min)   V(max)
0s        1.09V      1.369V     914.4mV
240.2ps   1.09V      1.369V     1.021V
530.5ps   1.137V     1.369V     2.328V
600.6ps   1.258V     1.369V     2.534V
840.8ps   2.203V     1.369V     3.186V
1.061ns   2.701V     1.38V      3.462V
1.411ns   3.157V     1.743V     3.546V
1.742ns   3.24V      2.383V     3.571V
2.092ns   3.266V     2.6V       3.585V
4.985ns   3.299V     2.699V     3.599V
[Rising Waveform]
R_fixture= 50.000000
V_fixture= 0.0
V_fixture_min= 0.0
V_fixture_max= 0.0
|time   V(typ)   V(min)   V(max)
0s        42.13uV    18.72uV    -458.3uV
500.5ps   -7.377mV   44.78uV    34.72mV
700.7ps   -12.92mV   46.32uV    189.7mV
1.031ns   100.1mV    -1.914mV   605.2mV
1.652ns   699.5mV    54.14mV    1.528V
2.102ns   1.201V     367.9mV    2.117V
2.472ns   1.557V     662.8mV    2.398V
3.053ns   1.919V     1.051V     2.564V
3.443ns   2.037V     1.201V     2.603V
4.985ns   2.159V     1.378V     2.651V
[Falling Waveform]
R_fixture= 50.000000
V_fixture= 3.300000
V_fixture_min= 2.700000
V_fixture_max= 3.600000
|time   V(typ)   V(min)   V(max)
0s        3.299V     2.699V     3.599V
540.5ps   3.31V      2.699V     3.578V
680.7ps   3.313V     2.699V     3.453V
1.031ns   3.254V     2.7V       2.918V
1.712ns   2.465V     2.671V     1.905V
2.222ns   1.842V     2.2V       1.359V
2.513ns   1.632V     1.908V     1.151V
3.083ns   1.323V     1.551V     1.006V
3.914ns   1.156V     1.432V     941.5mV
4.985ns   1.09V      1.369V     914.4mV
[Falling Waveform]
R_fixture= 50.000000
V_fixture= 0.0
V_fixture_min= 0.0
V_fixture_max= 0.0
|time   V(typ)   V(min)   V(max)
0s        2.159V     1.378V     2.651V
240.2ps   2.161V     1.378V     2.538V
580.6ps   2.049V     1.378V     1.525V
930.9ps   1.317V     1.378V     604mV
1.281ns   583.8mV    1.285V     141.1mV
1.672ns   161.8mV    839.8mV    35.54mV
2.102ns   47.48mV    311.1mV    6.563mV
2.382ns   23.69mV    143.4mV    3.152mV
3.143ns   5mV        26.61mV    339.8uV
4.985ns   42.13uV    18.72uV    -458.3uV
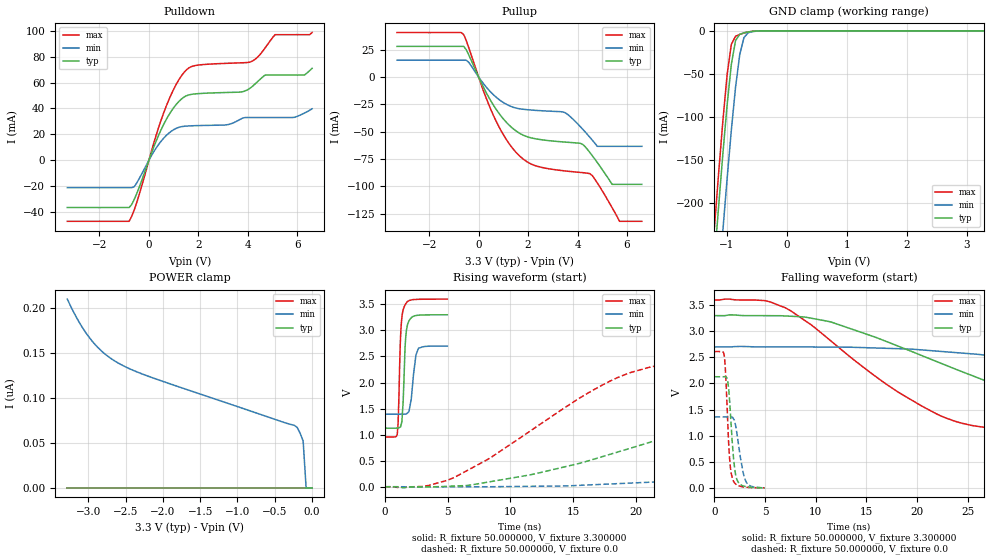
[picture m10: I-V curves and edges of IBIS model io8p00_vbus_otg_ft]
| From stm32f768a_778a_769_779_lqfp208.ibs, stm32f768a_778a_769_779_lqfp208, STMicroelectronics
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|   Model io8p00_vbus_otg_ft
[Model]  io8p00_vbus_otg_ft
Model_type I/O
Polarity   Non-Inverting
Enable   Active-Low
Vinl =   0.990000V
Vinh =   2.310000V
Vmeas =  1.650000V
Cref =   50.000000pF
Rref =   100.000000M
Vref =   0.0V
C_comp   3.304800pF   3.199300pF   3.429300pF
[Temperature Range]   25.000000   0.125000k   -40.000000
[Pullup Reference]   3.300000V   2.700000V   3.600000V
[Pulldown Reference]   0.0V   0.0V   0.0V
[POWER Clamp Reference]   3.300000V   2.700000V   3.600000V
[GND Clamp Reference]   0.0V   0.0V   0.0V
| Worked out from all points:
|   slope of the pulldown table from 0 to 0.495 V, typ, clamps not added: 20.9 ohm
|   slope of the pullup table from 0 to 0.495 V, typ, clamps not added: 22.6 ohm
|   GND clamp passes 1 mA (typ) near -0.61 V on its own axis
|   rising waveform, R_fixture 50.000000, V_fixture 3.300000: 20-80 % time 223ps typ, 350ps min, 206ps max; typ from 1.12 V to 3.3 V
|   rising waveform, R_fixture 50.000000, V_fixture 0.0: 20-80 % time 19.3ns typ, 47.3ns min, 10.3ns max; typ from 0 V to 2.13 V
|   falling waveform, R_fixture 50.000000, V_fixture 3.300000: 20-80 % time 18.4ns typ, 37.5ns min, 11.4ns max; typ from 3.3 V to 1.12 V
|   falling waveform, R_fixture 50.000000, V_fixture 0.0: 20-80 % time 481ps typ, 676ps min, 388ps max; typ from 2.13 V to 0 V
[Pulldown]
|Voltage   I(typ)   I(min)   I(max)
-3.3V     -36.41mA   -21.08mA   -47.04mA
-800mV    -36.41mA   -21.08mA   -47.04mA
-600mV    -30.48mA   -20.53mA   -38.65mA
700mV     31.4mA     19.11mA    41.71mA
1.2V      45.15mA    25.37mA    61.75mA
1.6V      50.35mA    26.5mA     71.06mA
3.1V      52.28mA    27.26mA    74.76mA
4.1V      55.7mA     32.99mA    75.81mA
4.7V      65.72mA    32.99mA    86.7mA
5.1V      65.72mA    32.99mA    96.91mA
6.3V      65.88mA    36.51mA    96.91mA
6.6V      70.94mA    39.72mA    98.51mA
[Pullup]
|Voltage   I(typ)   I(min)   I(max)
-3.3V     28.04mA    15.43mA    40.69mA
-700mV    28.04mA    15.43mA    40.69mA
-400mV    20.31mA    13.47mA    26.93mA
600mV     -25.77mA   -16.23mA   -35.14mA
1.6V      -50.64mA   -28.81mA   -70.96mA
3.5V      -59.53mA   -32.66mA   -85.92mA
4.2V      -61.44mA   -47.49mA   -87.46mA
4.5V      -69.06mA   -55.13mA   -88.4mA
4.8V      -78.22mA   -63.4mA    -96.84mA
5.4V      -98.2mA    -63.4mA    -119.6mA
5.7V      -98.2mA    -63.4mA    -132mA
6.6V      -98.2mA    -63.4mA    -132mA
[GND_clamp]
|Voltage   I(typ)   I(min)   I(max)
-3.3V     -2.322A    -2.4A      -2.296A
-1.2V     -265.6mA   -356.2mA   -227.3mA
-1.13V    -202.8mA   -293mA     -164.3mA
-1.06V    -142.3mA   -231.2mA   -104.3mA
-990mV    -86.15mA   -171.7mA   -51mA
-920mV    -39.05mA   -115.6mA   -15.71mA
-850mV    -11.4mA    -65.74mA   -6.366mA
-780mV    -4.046mA   -27.6mA    -4.153mA
-710mV    -2.285mA   -7.882mA   -2.591mA
-640mV    -1.291mA   -2.274mA   -1.367mA
-570mV    -618uA     -909.9uA   -567.3uA
3.28V     0A         0A         0A
[POWER_clamp]
|Voltage   I(typ)   I(min)   I(max)
-3.28V    0A         210.1nA    0A
-3.12V    0A         184.2nA    0A
-2.96V    0A         164.6nA    0A
-2.8V     0A         150.7nA    0A
-2.6V     0A         139nA      0A
-2.16V    0A         123.2nA    0A
-240mV    0A         69.7nA     0A
-200mV    0A         67.32nA    0A
-160mV    0A         60.72nA    0A
-120mV    0A         52.23nA    0A
-80mV     0A         0A         0A
0V        0A         0A         0A
[Ramp]
| variable   typ   min   max
dV/dt_r  1.27722/19.22882n   0.81552/47.32081n   1.56732/10.30493n
dV/dt_f  1.30704/18.40973n   0.78480/37.62340n   1.58790/11.37651n
R_load = 50.000000
[Rising Waveform]
R_fixture= 50.000000
V_fixture= 3.300000
V_fixture_min= 2.700000
V_fixture_max= 3.600000
|time   V(typ)   V(min)   V(max)
0s        1.124V     1.392V     953.5mV
991ps     1.126V     1.392V     1.003V
1.061ns   1.127V     1.392V     1.214V
1.281ns   1.171V     1.392V     2.992V
1.461ns   1.622V     1.391V     3.391V
1.552ns   2.215V     1.392V     3.456V
1.722ns   2.994V     1.396V     3.529V
2.032ns   3.221V     1.579V     3.579V
2.683ns   3.291V     2.656V     3.597V
4.985ns   3.3V       2.7V       3.6V
[Rising Waveform]
R_fixture= 50.000000
V_fixture= 0.0
V_fixture_min= 0.0
V_fixture_max= 0.0
|time   V(typ)   V(min)   V(max)
0s        7.268nV    356.2nV    4.785nV
5.506ns   13.45mV    -164.3uV   174.1mV
12.01ns   249.9mV    9.339mV    1.138V
19.52ns   735.4mV    69.84mV    2.186V
32.03ns   1.579V     228.2mV    2.544V
39.04ns   1.869V     348.6mV    2.575V
50.55ns   2.029V     586.6mV    2.602V
86.59ns   2.116V     1.138V     2.612V
157.7ns   2.13V      1.347V     2.612V
249.2ns   2.129V     1.359V     2.612V
[Falling Waveform]
R_fixture= 50.000000
V_fixture= 3.300000
V_fixture_min= 2.700000
V_fixture_max= 3.600000
|time   V(typ)   V(min)   V(max)
0s        3.3V       2.7V       3.6V
5.506ns   3.299V     2.7V       3.563V
11.51ns   3.178V     2.697V     2.812V
17.02ns   2.801V     2.674V     1.981V
22.52ns   2.374V     2.612V     1.364V
31.53ns   1.722V     2.432V     1.074V
46.55ns   1.275V     2.084V     997.9mV
64.06ns   1.182V     1.708V     968.8mV
88.09ns   1.144V     1.519V     956.4mV
249.2ns   1.124V     1.392V     953.5mV
[Falling Waveform]
R_fixture= 50.000000
V_fixture= 0.0
V_fixture_min= 0.0
V_fixture_max= 0.0
|time   V(typ)   V(min)   V(max)
0s        2.129V     1.359V     2.612V
981ps     2.13V      1.359V     2.511V
1.151ns   2.12V      1.358V     1.983V
1.311ns   2.033V     1.358V     1.246V
1.491ns   1.67V      1.36V      565.1mV
1.812ns   734.4mV    1.345V     159.6mV
2.182ns   178.7mV    1.087V     60.4mV
2.573ns   62.05mV    563.4mV    29.14mV
3.033ns   25.85mV    155.3mV    14.4mV
4.985ns   7.268nV    356.2nV    4.785nV
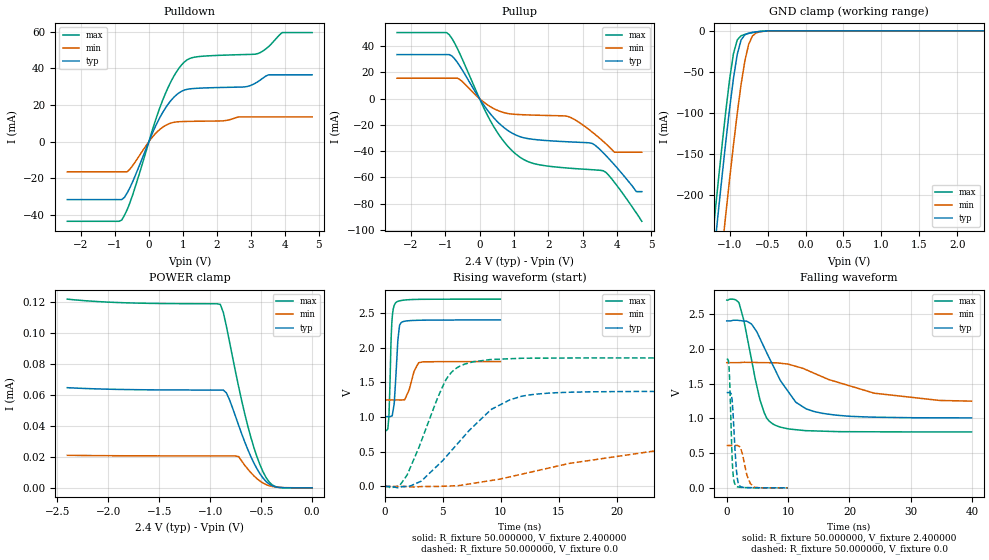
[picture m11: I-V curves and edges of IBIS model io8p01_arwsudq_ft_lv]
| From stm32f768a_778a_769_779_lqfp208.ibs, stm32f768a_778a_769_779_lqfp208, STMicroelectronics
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|   Model io8p01_arwsudq_ft_lv
[Model]  io8p01_arwsudq_ft_lv
Model_type I/O
Polarity   Non-Inverting
Enable   Active-Low
Vinl =   0.720000V
Vinh =   1.680000V
Vmeas =  1.200000V
Cref =   50.000000pF
Rref =   100.000000M
Vref =   0.0V
C_comp   2.818400pF   2.774300pF   2.917100pF
[Temperature Range]   25.000000   0.125000k   -40.000000
[Pullup Reference]   2.400000V   1.800000V   2.700000V
[Pulldown Reference]   0.0V   0.0V   0.0V
[POWER Clamp Reference]   2.400000V   1.800000V   2.700000V
[GND Clamp Reference]   0.0V   0.0V   0.0V
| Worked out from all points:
|   slope of the pulldown table from 0 to 0.36 V, typ, clamps not added: 25 ohm
|   slope of the pullup table from 0 to 0.36 V, typ, clamps not added: 27.7 ohm
|   GND clamp passes 1 mA (typ) near -0.62 V on its own axis
|   rising waveform, R_fixture 50.000000, V_fixture 2.400000: 20-80 % time 290ps typ, 616ps min, 206ps max; typ from 1.01 V to 2.4 V
|   rising waveform, R_fixture 50.000000, V_fixture 0.0: 20-80 % time 4.7ns typ, 11.9ns min, 2.65ns max; typ from 0 V to 1.37 V
|   falling waveform, R_fixture 50.000000, V_fixture 2.400000: 20-80 % time 5.26ns typ, 11.2ns min, 2.74ns max; typ from 2.4 V to 1.01 V
|   falling waveform, R_fixture 50.000000, V_fixture 0.0: 20-80 % time 542ps typ, 1ns min, 410ps max; typ from 1.37 V to 0 V
[Pulldown]
|Voltage   I(typ)   I(min)   I(max)
-2.4V     -31.67mA   -16.51mA   -43.52mA
-800mV    -31.67mA   -16.51mA   -42.87mA
-480mV    -21.98mA   -13.17mA   -29.21mA
80mV      3.63mA     1.966mA    5.013mA
480mV     18.16mA    8.738mA    26.02mA
800mV     25.38mA    10.72mA    37.77mA
1.12V     28.53mA    11.02mA    44.6mA
2.8V      29.84mA    13.5mA     47.53mA
3.2V      32.66mA    13.5mA     48.04mA
3.52V     36.46mA    13.5mA     51.85mA
3.92V     36.46mA    13.5mA     59.54mA
4.8V      36.46mA    13.5mA     59.54mA
[Pullup]
|Voltage   I(typ)   I(min)   I(max)
-2.4V     33.58mA    15.57mA    50.37mA
-960mV    33.58mA    15.57mA    50.37mA
-560mV    24.29mA    14.31mA    33.54mA
320mV     -11.75mA   -6.207mA   -17.08mA
960mV     -26.47mA   -11.82mA   -40.02mA
1.52V     -30.88mA   -12.51mA   -49.05mA
2.56V     -32.88mA   -13.49mA   -52.9mA
3.28V     -34.2mA    -25.53mA   -54.18mA
3.6V      -41.33mA   -32.62mA   -54.99mA
3.92V     -50.33mA   -40.8mA    -63.66mA
4.56V     -70.9mA    -40.8mA    -87.12mA
4.72V     -70.9mA    -40.8mA    -93.5mA
[GND_clamp]
|Voltage   I(typ)   I(min)   I(max)
-2.4V     -1.425A    -1.509A    -1.395A
-1.25V    -311.8mA   -402mA     -274.5mA
-1.2V     -266mA     -356.2mA   -228.4mA
-1.15V    -220.9mA   -310.9mA   -183.1mA
-1.1V     -176.9mA   -266.3mA   -139mA
-1.05V    -134.3mA   -222.6mA   -97.01mA
-950mV    -57.81mA   -139.1mA   -27.86mA
-900mV    -28.73mA   -100.5mA   -11.04mA
-850mV    -11.29mA   -65.69mA   -6.054mA
-750mV    -2.852mA   -16.6mA    -3.179mA
-600mV    -750uA     -1.167mA   -738.5uA
2.35V     0A         0A         0A
[POWER_clamp]
|Voltage   I(typ)   I(min)   I(max)
-2.4V     64.71uA    21.03uA    121.9uA
-1.86V    63.55uA    20.74uA    119.6uA
-900mV    63.18uA    20.63uA    118.5uA
-870mV    63.14uA    20.63uA    113.2uA
-840mV    61.36uA    20.62uA    104.3uA
-720mV    40.37uA    20.18uA    65.28uA
-630mV    24.69uA    12.08uA    39.85uA
-540mV    12.26uA    5.907uA    20uA
-480mV    6.236uA    3.061uA    10.23uA
-420mV    2.4uA      1.365uA    3.726uA
-360mV    667.9nA    564nA      839.6nA
0V        0A         0A         0A
[Ramp]
| variable   typ   min   max
dV/dt_r  0.82218/4.69992n   0.36517/11.91770n   1.11113/2.65163n
dV/dt_f  0.83706/5.26773n   0.32208/12.24907n   1.13717/2.73488n
R_load = 50.000000
[Rising Waveform]
R_fixture= 50.000000
V_fixture= 2.400000
V_fixture_min= 1.800000
V_fixture_max= 2.700000
|time   V(typ)   V(min)   V(max)
0s        1.006V     1.247V     804.7mV
260.3ps   1.006V     1.247V     830.5mV
340.3ps   1.006V     1.247V     973.9mV
600.6ps   1.015V     1.247V     2.333V
800.8ps   1.178V     1.247V     2.603V
940.9ps   1.546V     1.247V     2.647V
1.141ns   2.129V     1.247V     2.668V
1.502ns   2.37V      1.246V     2.682V
2.923ns   2.395V     1.783V     2.696V
9.97ns    2.4V       1.8V       2.7V
[Rising Waveform]
R_fixture= 50.000000
V_fixture= 0.0
V_fixture_min= 0.0
V_fixture_max= 0.0
|time   V(typ)   V(min)   V(max)
0s        179.5uV    73.73uV    513.7uV
1.281ns   -10.87mV   167.6uV    16.45mV
1.922ns   835.3uV    -2.445mV   164.6mV
3.123ns   74.9mV     -2.312mV   641.9mV
5.205ns   412.9mV    3.847mV    1.516V
6.887ns   732.4mV    25.04mV    1.763V
9.209ns   1.113V     86.59mV    1.83V
12.65ns   1.322V     208.7mV    1.849V
24.5ns    1.369V     541.3mV    1.852V
39.88ns   1.37V      609mV      1.852V
[Falling Waveform]
R_fixture= 50.000000
V_fixture= 2.400000
V_fixture_min= 1.800000
V_fixture_max= 2.700000
|time   V(typ)   V(min)   V(max)
0s        2.4V       1.8V       2.7V
2.002ns   2.407V     1.801V     2.661V
4.004ns   2.358V     1.805V     1.859V
5.445ns   2.142V     1.801V     1.257V
6.486ns   1.948V     1.8V       1.009V
7.688ns   1.732V     1.799V     910.3mV
11.21ns   1.236V     1.749V     836.9mV
14.17ns   1.099V     1.651V     819mV
24.02ns   1.016V     1.361V     806.3mV
39.88ns   1.006V     1.247V     804.7mV
[Falling Waveform]
R_fixture= 50.000000
V_fixture= 0.0
V_fixture_min= 0.0
V_fixture_max= 0.0
|time   V(typ)   V(min)   V(max)
0s        1.37V      609mV      1.852V
380.4ps   1.37V      609.1mV    1.729V
880.9ps   1.263V     608.9mV    438.8mV
1.081ns   989.8mV    608.5mV    156.7mV
1.361ns   528.5mV    608.7mV    48.96mV
1.722ns   138.9mV    610.9mV    16.84mV
2.202ns   21.79mV    585mV      7.306mV
3.303ns   3.586mV    177.2mV    2.961mV
4.505ns   1.786mV    9.727mV    1.237mV
9.97ns    179.5uV    73.73uV    513.7uV
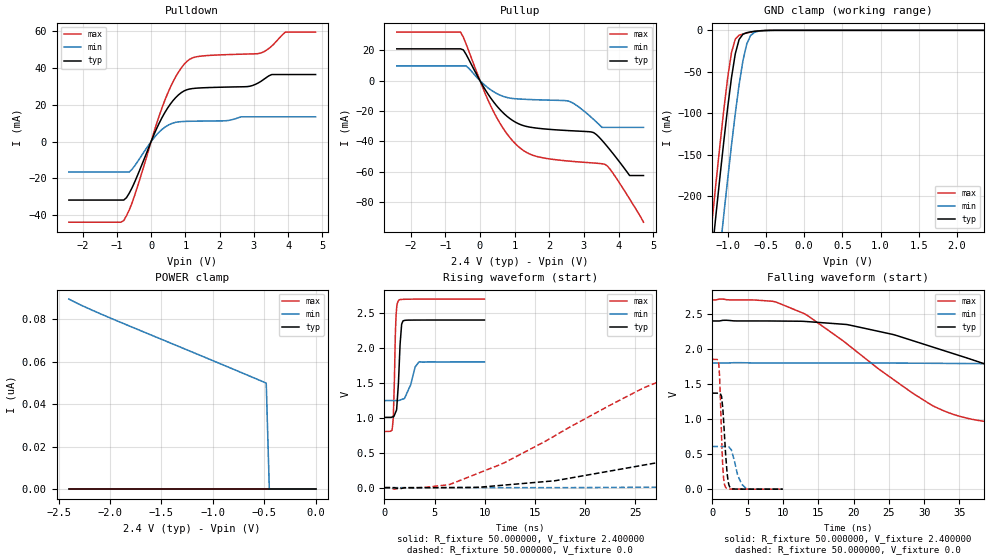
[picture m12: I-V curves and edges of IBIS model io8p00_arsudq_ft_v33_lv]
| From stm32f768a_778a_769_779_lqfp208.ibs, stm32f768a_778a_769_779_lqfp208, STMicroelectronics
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|   Model io8p00_arsudq_ft_v33_lv
[Model]  io8p00_arsudq_ft_v33_lv
Model_type I/O
Polarity   Non-Inverting
Enable   Active-Low
Vinl =   0.720000V
Vinh =   1.680000V
Vmeas =  1.200000V
Cref =   50.000000pF
Rref =   100.000000M
Vref =   0.0V
C_comp   2.238700pF   2.180600pF   2.332300pF
[Temperature Range]   25.000000   0.125000k   -40.000000
[Pullup Reference]   2.400000V   1.800000V   2.700000V
[Pulldown Reference]   0.0V   0.0V   0.0V
[POWER Clamp Reference]   2.400000V   1.800000V   2.700000V
[GND Clamp Reference]   0.0V   0.0V   0.0V
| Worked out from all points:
|   slope of the pulldown table from 0 to 0.36 V, typ, clamps not added: 25 ohm
|   slope of the pullup table from 0 to 0.36 V, typ, clamps not added: 27.7 ohm
|   GND clamp passes 1 mA (typ) near -0.62 V on its own axis
|   rising waveform, R_fixture 50.000000, V_fixture 2.400000: 20-80 % time 302ps typ, 741ps min, 198ps max; typ from 1.01 V to 2.4 V
|   rising waveform, R_fixture 50.000000, V_fixture 0.0: 20-80 % time 30.9ns typ, 81.7ns min, 14.6ns max; typ from 0 V to 1.37 V
|   falling waveform, R_fixture 50.000000, V_fixture 2.400000: 20-80 % time 29.6ns typ, 81.3ns min, 15.7ns max; typ from 2.4 V to 1.01 V
|   falling waveform, R_fixture 50.000000, V_fixture 0.0: 20-80 % time 534ps typ, 1.03ns min, 386ps max; typ from 1.37 V to 0 V
[Pulldown]
|Voltage   I(typ)   I(min)   I(max)
-2.4V     -31.73mA   -16.51mA   -43.74mA
-800mV    -31.73mA   -16.51mA   -42.87mA
-480mV    -21.98mA   -13.17mA   -29.21mA
80mV      3.63mA     1.966mA    5.014mA
480mV     18.16mA    8.738mA    26.02mA
800mV     25.38mA    10.72mA    37.77mA
1.12V     28.53mA    11.02mA    44.6mA
2.8V      29.84mA    13.47mA    47.53mA
3.2V      32.64mA    13.47mA    48.05mA
3.52V     36.39mA    13.47mA    51.83mA
3.92V     36.39mA    13.47mA    59.44mA
4.8V      36.39mA    13.47mA    59.44mA
[Pullup]
|Voltage   I(typ)   I(min)   I(max)
-2.4V     20.89mA    9.66mA     31.9mA
-560mV    20.89mA    9.66mA     31.9mA
-400mV    17.28mA    9.66mA     24.07mA
320mV     -11.75mA   -6.207mA   -17.08mA
640mV     -20.52mA   -10.1mA    -30.35mA
960mV     -26.47mA   -11.82mA   -40.02mA
1.52V     -30.88mA   -12.51mA   -49.05mA
2.56V     -32.88mA   -13.48mA   -52.9mA
3.28V     -34.19mA   -25.51mA   -54.18mA
3.6V      -41.31mA   -30.76mA   -54.97mA
4.32V     -62.44mA   -30.76mA   -77.81mA
4.72V     -62.44mA   -30.76mA   -93.1mA
[GND_clamp]
|Voltage   I(typ)   I(min)   I(max)
-2.4V     -1.425A    -1.508A    -1.394A
-1.25V    -311.2mA   -401.9mA   -273.3mA
-1.2V     -265.4mA   -356.1mA   -227.2mA
-1.15V    -220.4mA   -310.8mA   -181.9mA
-1.1V     -176.3mA   -266.2mA   -137.9mA
-1.05V    -133.8mA   -222.5mA   -95.87mA
-950mV    -57.3mA    -138.9mA   -26.98mA
-900mV    -28.27mA   -100.4mA   -10.59mA
-850mV    -11.01mA   -65.54mA   -5.958mA
-750mV    -2.834mA   -16.5mA    -3.178mA
-600mV    -750uA     -1.164mA   -738.3uA
2.35V     0A         0A         0A
[POWER_clamp]
|Voltage   I(typ)   I(min)   I(max)
-2.4V     0A         89.62nA    0A
-2.04V    0A         81.57nA    0A
-480mV    0A         50.01nA    0A
-450mV    0A         0A         0A
0V        0A         0A         0A
[Ramp]
| variable   typ   min   max
dV/dt_r  0.82212/30.90078n   0.36308/83.79692n   1.11108/14.57424n
dV/dt_f  0.83664/29.58666n   0.32682/81.70577n   1.13714/15.64602n
R_load = 50.000000
[Rising Waveform]
R_fixture= 50.000000
V_fixture= 2.400000
V_fixture_min= 1.800000
V_fixture_max= 2.700000
|time   V(typ)   V(min)   V(max)
0s        1.006V     1.247V     804.6mV
780.8ps   1.011V     1.247V     846.8mV
880.9ps   1.016V     1.247V     996.9mV
1.161ns   1.095V     1.247V     2.467V
1.401ns   1.515V     1.246V     2.677V
1.562ns   2.057V     1.254V     2.692V
1.722ns   2.343V     1.263V     2.695V
1.862ns   2.389V     1.27V      2.696V
3.463ns   2.4V       1.803V     2.699V
9.97ns    2.4V       1.8V       2.7V
[Rising Waveform]
R_fixture= 50.000000
V_fixture= 0.0
V_fixture_min= 0.0
V_fixture_max= 0.0
|time   V(typ)   V(min)   V(max)
0s        7.79nV     249.6nV    27.46nV
6.507ns   922.5uV    -67.36uV   44.92mV
17.02ns   98.67mV    89.24uV    744.5mV
28.53ns   390.6mV    7.07mV     1.568V
34.53ns   558.7mV    13.46mV    1.716V
42.54ns   790mV      41mV       1.791V
59.56ns   1.173V     99.52mV    1.839V
79.58ns   1.315V     192.9mV    1.847V
153.2ns   1.368V     510.7mV    1.852V
249.2ns   1.37V      609.1mV    1.852V
[Falling Waveform]
R_fixture= 50.000000
V_fixture= 2.400000
V_fixture_min= 1.800000
V_fixture_max= 2.700000
|time   V(typ)   V(min)   V(max)
0s        2.4V       1.8V       2.7V
8.509ns   2.4V       1.8V       2.681V
13.01ns   2.394V     1.8V       2.505V
19.52ns   2.34V      1.8V       2.036V
31.03ns   2.034V     1.796V     1.201V
42.54ns   1.653V     1.779V     920.4mV
62.56ns   1.211V     1.705V     840.5mV
80.08ns   1.095V     1.608V     818.4mV
157.2ns   1.013V     1.324V     805.3mV
249.2ns   1.006V     1.247V     804.6mV
[Falling Waveform]
R_fixture= 50.000000
V_fixture= 0.0
V_fixture_min= 0.0
V_fixture_max= 0.0
|time   V(typ)   V(min)   V(max)
0s        1.37V      609.1mV    1.852V
900.9ps   1.371V     608.9mV    1.791V
1.101ns   1.367V     608.8mV    1.401V
1.481ns   1.147V     608.5mV    311.3mV
1.862ns   523.4mV    609.4mV    29.43mV
2.242ns   107.2mV    606.6mV    5.162mV
2.643ns   13.51mV    566.2mV    1.813mV
3.584ns   1.155mV    200.8mV    683.7uV
4.805ns   363.1uV    8.575mV    348.1uV
9.97ns    7.79nV     249.6nV    27.46nV
